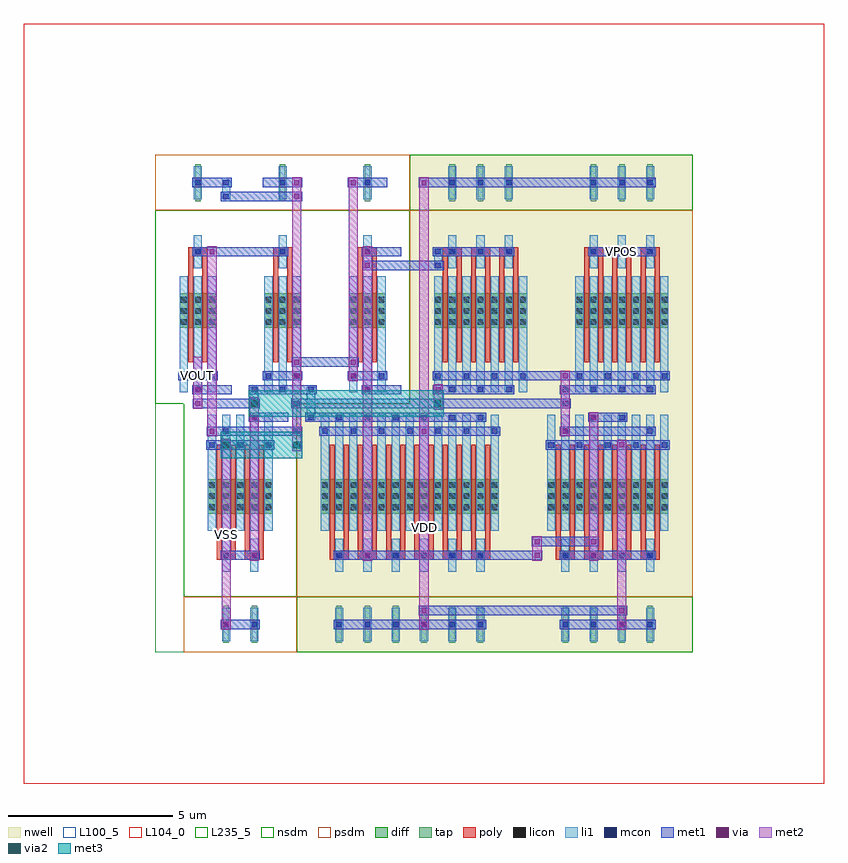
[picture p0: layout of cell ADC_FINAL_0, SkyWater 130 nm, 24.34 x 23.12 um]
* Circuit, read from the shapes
.subckt ADC_FINAL_0 VDD VOUT VPOS VSS
XM1 VOUT n1 VOUT VSS sky130_fd_pr__nfet_01v8 w=1.05 l=0.15 m=2
XM2 n1 n2 VSS VSS sky130_fd_pr__nfet_01v8 w=1.05 l=0.15 m=2
XM3 n2 n2 VSS VSS sky130_fd_pr__nfet_01v8 w=1.05 l=0.15 m=2
XM4 VOUT n1 VSS VSS sky130_fd_pr__nfet_01v8 w=1.05 l=0.15 m=2
XM5 n3 n3 VSS VSS sky130_fd_pr__nfet_01v8 w=1.05 l=0.15 m=2
XM6 VOUT n3 VDD VDD sky130_fd_pr__pfet_01v8 w=1.05 l=0.15 m=12
XM7 n2 n3 n4 VDD sky130_fd_pr__pfet_01v8 w=1.05 l=0.15 m=6
XM8 n4 n3 VDD VDD sky130_fd_pr__pfet_01v8 w=1.05 l=0.15 m=4
XM9 n3 n3 VDD VDD sky130_fd_pr__pfet_01v8 w=1.05 l=0.15 m=4
XM10 n1 VPOS n4 VDD sky130_fd_pr__pfet_01v8 w=1.05 l=0.15 m=6
.ends

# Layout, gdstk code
from math import pi, radians
import gdstk
lib = gdstk.Library(unit=1e-6, precision=1e-09)
def R(c, l, rs):  # rectangles x0, y0, x1, y1
    for r in rs: c.add(gdstk.rectangle(r[:2], r[2:], *l))
def A(c, l, x, y, w, h, nx, ny, dx, dy):  # array of equal rectangles
    R(c, l, [(x+i*dx, y+j*dy, x+i*dx+w, y+j*dy+h) for i in range(nx) for j in range(ny)])
def P(c, l, *ps):  # polygons
    for p in ps: c.add(gdstk.Polygon(p, *l))
nwell = (64, 20)
diff = (65, 20)
tap = (65, 44)
poly = (66, 20)
licon = (66, 44)
li1 = (67, 20)
mcon = (67, 44)
met1 = (68, 20)
via = (68, 44)
met2 = (69, 20)
via2 = (69, 44)
met3 = (70, 20)
nsdm = (93, 44)
psdm = (94, 20)
L100_5 = (100, 5)
L104_0 = (104, 0)
L235_5 = (235, 5)

scm_pmos_42993348_x2_y1_ = lib.new_cell('SCM_PMOS_42993348_X2_Y1_1678492655_1678492654')
R(scm_pmos_42993348_x2_y1_, nwell, [(0,0,5.16,7.56)])
R(scm_pmos_42993348_x2_y1_, diff, [(0.735,2.31,4.425,3.36)])
A(scm_pmos_42993348_x2_y1_, tap, 1.205, 6.16, 0.17, 1.12, 4, 1, 0.86, 0)
A(scm_pmos_42993348_x2_y1_, poly, 1, 1.26, 0.15, 3.36, 8, 1, 0.43, 0)
A(scm_pmos_42993348_x2_y1_, poly, 1, 4.485, 0.58, 0.27, 4, 1, 0.86, 0)
A(scm_pmos_42993348_x2_y1_, licon, 0.775, 2.39, 0.17, 0.17, 3, 3, 0.43, 0.34)
A(scm_pmos_42993348_x2_y1_, licon, 1.635, 2.39, 0.17, 0.17, 3, 3, 0.43, 0.34)
A(scm_pmos_42993348_x2_y1_, licon, 2.495, 2.39, 0.17, 0.17, 3, 3, 0.43, 0.34)
A(scm_pmos_42993348_x2_y1_, licon, 3.355, 2.39, 0.17, 0.17, 3, 3, 0.43, 0.34)
A(scm_pmos_42993348_x2_y1_, licon, 1.205, 4.535, 0.17, 0.17, 4, 2, 0.86, 2.1)
A(scm_pmos_42993348_x2_y1_, li1, 0.735, 0.335, 0.25, 3.53, 9, 1, 0.43, 0)
A(scm_pmos_42993348_x2_y1_, li1, 1.165, 4.115, 0.25, 1.01, 4, 2, 0.86, 2.1)
A(scm_pmos_42993348_x2_y1_, mcon, 0.775, 1.175, 0.17, 0.17, 5, 1, 0.86, 0)
A(scm_pmos_42993348_x2_y1_, mcon, 1.205, 4.535, 0.17, 0.17, 4, 2, 0.86, 2.1)
R(scm_pmos_42993348_x2_y1_, mcon, [(2.065,0.335,2.235,0.505), (2.925,0.335,3.095,0.505), (1.205,0.755,1.375,0.925), (3.785,0.755,3.955,0.925)])
R(scm_pmos_42993348_x2_y1_, met1, [(1.98,0.28,3.18,0.56), (1.12,0.7,4.04,0.98), (0.69,1.12,4.47,1.4), (1.12,4.48,4.04,4.76), (1.12,6.58,4.04,6.86)])
R(scm_pmos_42993348_x2_y1_, via, [(2.075,0.345,2.225,0.495), (2.935,1.185,3.085,1.335), (2.075,4.545,2.225,4.695), (2.935,6.645,3.085,6.795)])
R(scm_pmos_42993348_x2_y1_, met2, [(2.01,0.26,2.29,4.78), (2.87,1.1,3.15,6.88)])
R(scm_pmos_42993348_x2_y1_, nsdm, [(0,5.88,5.16,7.56)])
R(scm_pmos_42993348_x2_y1_, psdm, [(0,0,5.16,5.88)])
R(scm_pmos_42993348_x2_y1_, L100_5, [(0,0,5.16,7.56)])

pmos_s_81354572_x6_y1_16 = lib.new_cell('PMOS_S_81354572_X6_Y1_1678492654_1678492654')
R(pmos_s_81354572_x6_y1_16, nwell, [(0,0,6.88,7.56)])
R(pmos_s_81354572_x6_y1_16, diff, [(0.735,2.31,6.145,3.36)])
A(pmos_s_81354572_x6_y1_16, tap, 1.205, 6.16, 0.17, 1.12, 6, 1, 0.86, 0)
A(pmos_s_81354572_x6_y1_16, poly, 1, 1.26, 0.15, 3.36, 12, 1, 0.43, 0)
A(pmos_s_81354572_x6_y1_16, poly, 1, 4.485, 0.58, 0.27, 6, 1, 0.86, 0)
A(pmos_s_81354572_x6_y1_16, licon, 0.775, 2.39, 0.17, 0.17, 3, 3, 0.43, 0.34)
A(pmos_s_81354572_x6_y1_16, licon, 1.635, 2.39, 0.17, 0.17, 3, 3, 0.43, 0.34)
A(pmos_s_81354572_x6_y1_16, licon, 2.495, 2.39, 0.17, 0.17, 3, 3, 0.43, 0.34)
A(pmos_s_81354572_x6_y1_16, licon, 3.355, 2.39, 0.17, 0.17, 3, 3, 0.43, 0.34)
A(pmos_s_81354572_x6_y1_16, licon, 4.215, 2.39, 0.17, 0.17, 3, 3, 0.43, 0.34)
A(pmos_s_81354572_x6_y1_16, licon, 5.075, 2.39, 0.17, 0.17, 3, 3, 0.43, 0.34)
A(pmos_s_81354572_x6_y1_16, licon, 1.205, 4.535, 0.17, 0.17, 6, 2, 0.86, 2.1)
A(pmos_s_81354572_x6_y1_16, li1, 0.735, 0.335, 0.25, 3.53, 13, 1, 0.43, 0)
A(pmos_s_81354572_x6_y1_16, li1, 1.165, 4.115, 0.25, 1.01, 6, 2, 0.86, 2.1)
A(pmos_s_81354572_x6_y1_16, mcon, 1.205, 0.335, 0.17, 0.17, 6, 2, 0.86, 4.2)
A(pmos_s_81354572_x6_y1_16, mcon, 0.775, 0.755, 0.17, 0.17, 7, 1, 0.86, 0)
A(pmos_s_81354572_x6_y1_16, mcon, 1.205, 6.635, 0.17, 0.17, 6, 1, 0.86, 0)
R(pmos_s_81354572_x6_y1_16, met1, [(1.12,0.28,5.76,0.56), (0.69,0.7,6.19,0.98), (1.12,4.48,5.76,4.76), (1.12,6.58,5.76,6.86)])
R(pmos_s_81354572_x6_y1_16, via, [(3.795,0.765,3.945,0.915), (3.795,6.645,3.945,6.795)])
R(pmos_s_81354572_x6_y1_16, met2, [(3.73,0.68,4.01,6.88)])
R(pmos_s_81354572_x6_y1_16, nsdm, [(0,5.88,6.88,7.56)])
R(pmos_s_81354572_x6_y1_16, psdm, [(0,0,6.88,5.88)])
R(pmos_s_81354572_x6_y1_16, L100_5, [(0,0,6.88,7.56)])

cmb_pmos_2_81333957_0_0_ = lib.new_cell('CMB_PMOS_2_81333957_0_0_1678492654')
R(cmb_pmos_2_81333957_0_0_, met1, [(7.15,4.06,7.47,4.34), (7.15,4.06,7.47,4.34), (7.31,4.06,9.03,4.34), (8.87,4.06,9.19,4.34), (8.87,4.06,9.19,4.34), (5.59,4.48,7.31,4.76), (7.15,4.48,7.47,4.76), (7.15,4.48,7.47,4.76), (3.71,6.16,4.03,6.44), (3.71,6.16,4.03,6.44), (3.87,6.16,9.89,6.44), (9.73,6.16,10.05,6.44), (9.73,6.16,10.05,6.44)])
P(cmb_pmos_2_81333957_0_0_, met1, [(0,0),(0,0),(0,0),(0,0)],
  [(0,0),(0,0),(0,0),(0,0)],
  [(0,0),(0,0),(0,0),(0,0)])
R(cmb_pmos_2_81333957_0_0_, via, [(7.235,4.125,7.385,4.275), (7.235,4.125,7.385,4.275), (8.955,4.125,9.105,4.275), (8.955,4.125,9.105,4.275), (7.235,4.545,7.385,4.695), (7.235,4.545,7.385,4.695), (3.795,6.225,3.945,6.375), (3.795,6.225,3.945,6.375), (9.815,6.225,9.965,6.375), (9.815,6.225,9.965,6.375)])
R(cmb_pmos_2_81333957_0_0_, met2, [(7.17,4.04,7.45,4.36), (7.17,4.04,7.45,4.36), (8.89,4.04,9.17,4.36), (8.89,4.04,9.17,4.36), (7.17,4.2,7.45,4.62), (7.17,4.46,7.45,4.78), (7.17,4.46,7.45,4.78), (3.73,6.14,4.01,6.46), (3.73,6.14,4.01,6.46), (9.75,6.14,10.03,6.46), (9.75,6.14,10.03,6.46)])
P(cmb_pmos_2_81333957_0_0_, met2, [(0,0),(0,0),(0,0),(0,0)],
  [(0,0),(0,0),(0,0),(0,0)],
  [(0,0),(0,0),(0,0),(0,0)])
R(cmb_pmos_2_81333957_0_0_, L235_5, [(0,0,12.04,7.56)])
cmb_pmos_2_81333957_0_0_.add(gdstk.Reference(scm_pmos_42993348_x2_y1_, (6.88,0)))
cmb_pmos_2_81333957_0_0_.add(gdstk.Reference(pmos_s_81354572_x6_y1_16, (0,0)))

scm_nmos_43308780_x1_y1_ = lib.new_cell('SCM_NMOS_43308780_X1_Y1_1678492659')
R(scm_nmos_43308780_x1_y1_, diff, [(0.735,2.31,2.705,3.36)])
R(scm_nmos_43308780_x1_y1_, tap, [(1.205,6.16,1.375,7.28), (2.065,6.16,2.235,7.28)])
A(scm_nmos_43308780_x1_y1_, poly, 1, 1.26, 0.15, 3.36, 4, 1, 0.43, 0)
R(scm_nmos_43308780_x1_y1_, poly, [(1,4.485,1.58,4.755), (1.86,4.485,2.44,4.755)])
A(scm_nmos_43308780_x1_y1_, licon, 0.775, 2.39, 0.17, 0.17, 3, 3, 0.43, 0.34)
A(scm_nmos_43308780_x1_y1_, licon, 1.635, 2.39, 0.17, 0.17, 3, 3, 0.43, 0.34)
R(scm_nmos_43308780_x1_y1_, licon, [(1.205,4.535,1.375,4.705), (2.065,4.535,2.235,4.705), (1.205,6.635,1.375,6.805), (2.065,6.635,2.235,6.805)])
A(scm_nmos_43308780_x1_y1_, li1, 0.735, 0.335, 0.25, 3.53, 5, 1, 0.43, 0)
R(scm_nmos_43308780_x1_y1_, li1, [(1.165,4.115,1.415,5.125), (2.025,4.115,2.275,5.125), (1.165,6.215,1.415,7.225), (2.025,6.215,2.275,7.225)])
A(scm_nmos_43308780_x1_y1_, mcon, 0.775, 1.175, 0.17, 0.17, 3, 1, 0.86, 0)
R(scm_nmos_43308780_x1_y1_, mcon, [(1.205,0.335,1.375,0.505), (2.065,0.755,2.235,0.925), (1.205,4.535,1.375,4.705), (2.065,4.535,2.235,4.705), (1.205,6.635,1.375,6.805), (2.065,6.635,2.235,6.805)])
R(scm_nmos_43308780_x1_y1_, met1, [(0.26,0.28,1.46,0.56), (1.12,0.7,2.32,0.98), (0.69,1.12,2.75,1.4), (1.12,4.48,2.32,4.76), (1.12,6.58,2.32,6.86)])
R(scm_nmos_43308780_x1_y1_, via, [(1.215,0.345,1.365,0.495), (2.075,1.185,2.225,1.335), (1.215,4.545,1.365,4.695), (2.075,6.645,2.225,6.795)])
R(scm_nmos_43308780_x1_y1_, met2, [(1.15,0.26,1.43,4.78), (2.01,1.1,2.29,6.88)])
R(scm_nmos_43308780_x1_y1_, nsdm, [(0,0,3.44,5.88)])
R(scm_nmos_43308780_x1_y1_, psdm, [(0,5.88,3.44,7.56)])
R(scm_nmos_43308780_x1_y1_, L100_5, [(0,0,3.44,7.56)])

dcl_nmos_s_28285743_x1_y = lib.new_cell('DCL_NMOS_S_28285743_X1_Y1_1678492656')
R(dcl_nmos_s_28285743_x1_y, diff, [(0.735,2.31,1.845,3.36)])
R(dcl_nmos_s_28285743_x1_y, tap, [(1.205,6.16,1.375,7.28)])
R(dcl_nmos_s_28285743_x1_y, poly, [(1,1.26,1.15,4.62), (1.43,1.26,1.58,4.62), (1,4.485,1.58,4.755)])
A(dcl_nmos_s_28285743_x1_y, licon, 0.775, 2.39, 0.17, 0.17, 3, 3, 0.43, 0.34)
R(dcl_nmos_s_28285743_x1_y, licon, [(1.205,4.535,1.375,4.705), (1.205,6.635,1.375,6.805)])
A(dcl_nmos_s_28285743_x1_y, li1, 0.735, 0.335, 0.25, 3.53, 3, 1, 0.43, 0)
R(dcl_nmos_s_28285743_x1_y, li1, [(1.165,4.115,1.415,5.125), (1.165,6.215,1.415,7.225)])
R(dcl_nmos_s_28285743_x1_y, mcon, [(1.205,0.335,1.375,0.505), (0.775,0.755,0.945,0.925), (1.635,0.755,1.805,0.925), (1.205,4.535,1.375,4.705), (1.205,6.635,1.375,6.805)])
R(dcl_nmos_s_28285743_x1_y, met1, [(0.26,0.28,1.46,0.56), (0.69,0.7,1.89,0.98), (0.26,4.48,1.46,4.76), (0.69,6.58,1.89,6.86)])
R(dcl_nmos_s_28285743_x1_y, via, [(1.215,0.345,1.365,0.495), (1.645,0.765,1.795,0.915), (1.215,4.545,1.365,4.695), (1.645,6.645,1.795,6.795)])
R(dcl_nmos_s_28285743_x1_y, met2, [(1.15,0.26,1.43,4.78), (1.58,0.68,1.86,6.88)])
R(dcl_nmos_s_28285743_x1_y, nsdm, [(0,0,2.58,5.88)])
R(dcl_nmos_s_28285743_x1_y, psdm, [(0,5.88,2.58,7.56)])
R(dcl_nmos_s_28285743_x1_y, L100_5, [(0,0,2.58,7.56)])

nmos_s_54487678_x1_y1_16 = lib.new_cell('NMOS_S_54487678_X1_Y1_1678492657')
R(nmos_s_54487678_x1_y1_16, diff, [(0.735,2.31,1.845,3.36)])
R(nmos_s_54487678_x1_y1_16, tap, [(1.205,6.16,1.375,7.28)])
R(nmos_s_54487678_x1_y1_16, poly, [(1,1.26,1.15,4.62), (1.43,1.26,1.58,4.62), (1,4.485,1.58,4.755)])
A(nmos_s_54487678_x1_y1_16, licon, 0.775, 2.39, 0.17, 0.17, 3, 3, 0.43, 0.34)
R(nmos_s_54487678_x1_y1_16, licon, [(1.205,4.535,1.375,4.705), (1.205,6.635,1.375,6.805)])
A(nmos_s_54487678_x1_y1_16, li1, 0.735, 0.335, 0.25, 3.53, 3, 1, 0.43, 0)
R(nmos_s_54487678_x1_y1_16, li1, [(1.165,4.115,1.415,5.125), (1.165,6.215,1.415,7.225)])
R(nmos_s_54487678_x1_y1_16, mcon, [(1.205,0.335,1.375,0.505), (0.775,0.755,0.945,0.925), (1.635,0.755,1.805,0.925), (1.205,4.535,1.375,4.705), (1.205,6.635,1.375,6.805)])
R(nmos_s_54487678_x1_y1_16, met1, [(0.26,0.28,1.46,0.56), (0.69,0.7,1.89,0.98), (0.26,4.48,1.46,4.76), (0.69,6.58,1.89,6.86)])
R(nmos_s_54487678_x1_y1_16, via, [(1.645,0.765,1.795,0.915), (1.645,6.645,1.795,6.795)])
R(nmos_s_54487678_x1_y1_16, met2, [(1.58,0.68,1.86,6.88)])
R(nmos_s_54487678_x1_y1_16, nsdm, [(0,0,2.58,5.88)])
R(nmos_s_54487678_x1_y1_16, psdm, [(0,5.88,2.58,7.56)])
R(nmos_s_54487678_x1_y1_16, L100_5, [(0,0,2.58,7.56)])

dcap_nmos_b_17613965_x1_ = lib.new_cell('DCAP_NMOS_B_17613965_X1_Y1_1678492655')
R(dcap_nmos_b_17613965_x1_, diff, [(0.735,2.31,1.845,3.36)])
R(dcap_nmos_b_17613965_x1_, tap, [(1.205,6.16,1.375,7.28)])
R(dcap_nmos_b_17613965_x1_, poly, [(1,1.26,1.15,4.62), (1.43,1.26,1.58,4.62), (1,4.485,1.58,4.755)])
A(dcap_nmos_b_17613965_x1_, licon, 0.775, 2.39, 0.17, 0.17, 3, 3, 0.43, 0.34)
R(dcap_nmos_b_17613965_x1_, licon, [(1.205,4.535,1.375,4.705), (1.205,6.635,1.375,6.805)])
A(dcap_nmos_b_17613965_x1_, li1, 0.735, 0.335, 0.25, 3.53, 3, 1, 0.43, 0)
R(dcap_nmos_b_17613965_x1_, li1, [(1.165,4.115,1.415,5.125), (1.165,6.215,1.415,7.225)])
R(dcap_nmos_b_17613965_x1_, mcon, [(1.205,0.335,1.375,0.505), (0.775,0.755,0.945,0.925), (1.635,0.755,1.805,0.925), (1.205,4.535,1.375,4.705), (1.205,6.635,1.375,6.805)])
R(dcap_nmos_b_17613965_x1_, met1, [(0.26,0.28,1.46,0.56), (0.69,0.7,1.89,0.98), (0.26,4.48,1.46,4.76), (0.26,6.58,1.46,6.86)])
R(dcap_nmos_b_17613965_x1_, via, [(1.215,0.345,1.365,0.495), (1.215,0.765,1.365,0.915)])
R(dcap_nmos_b_17613965_x1_, met2, [(1.15,0.26,1.43,1.42)])
R(dcap_nmos_b_17613965_x1_, nsdm, [(0,0,2.58,5.88)])
R(dcap_nmos_b_17613965_x1_, psdm, [(0,5.88,2.58,7.56)])
R(dcap_nmos_b_17613965_x1_, L100_5, [(0,0,2.58,7.56)])

pmos_4t_25753472_x3_y1_1 = lib.new_cell('PMOS_4T_25753472_X3_Y1_1678492658')
R(pmos_4t_25753472_x3_y1_1, nwell, [(0,0,4.3,7.56)])
R(pmos_4t_25753472_x3_y1_1, diff, [(0.735,2.31,3.565,3.36)])
A(pmos_4t_25753472_x3_y1_1, tap, 1.205, 6.16, 0.17, 1.12, 3, 1, 0.86, 0)
A(pmos_4t_25753472_x3_y1_1, poly, 1, 1.26, 0.15, 3.36, 6, 1, 0.43, 0)
A(pmos_4t_25753472_x3_y1_1, poly, 1, 4.485, 0.58, 0.27, 3, 1, 0.86, 0)
A(pmos_4t_25753472_x3_y1_1, licon, 0.775, 2.39, 0.17, 0.17, 3, 3, 0.43, 0.34)
A(pmos_4t_25753472_x3_y1_1, licon, 1.635, 2.39, 0.17, 0.17, 3, 3, 0.43, 0.34)
A(pmos_4t_25753472_x3_y1_1, licon, 2.495, 2.39, 0.17, 0.17, 3, 3, 0.43, 0.34)
A(pmos_4t_25753472_x3_y1_1, licon, 1.205, 4.535, 0.17, 0.17, 3, 2, 0.86, 2.1)
A(pmos_4t_25753472_x3_y1_1, li1, 0.735, 0.335, 0.25, 3.53, 7, 1, 0.43, 0)
A(pmos_4t_25753472_x3_y1_1, li1, 1.165, 4.115, 0.25, 1.01, 3, 2, 0.86, 2.1)
A(pmos_4t_25753472_x3_y1_1, mcon, 1.205, 0.335, 0.17, 0.17, 3, 2, 0.86, 4.2)
A(pmos_4t_25753472_x3_y1_1, mcon, 0.775, 0.755, 0.17, 0.17, 4, 1, 0.86, 0)
A(pmos_4t_25753472_x3_y1_1, mcon, 1.205, 6.635, 0.17, 0.17, 3, 1, 0.86, 0)
R(pmos_4t_25753472_x3_y1_1, met1, [(1.12,0.28,3.18,0.56), (0.69,0.7,3.61,0.98), (1.12,4.48,3.18,4.76), (1.12,6.58,3.18,6.86)])
R(pmos_4t_25753472_x3_y1_1, nsdm, [(0,5.88,4.3,7.56)])
R(pmos_4t_25753472_x3_y1_1, psdm, [(0,0,4.3,5.88)])
R(pmos_4t_25753472_x3_y1_1, L100_5, [(0,0,4.3,7.56)])

adc_final_0 = lib.new_cell('ADC_FINAL_0')
R(adc_final_0, li1, [(4.175,6.635,4.425,6.805), (4.175,6.635,4.425,6.805), (4.175,6.72,4.425,7.56), (4.605,7.055,4.855,7.225), (4.605,7.055,4.855,7.225), (4.605,7.14,4.855,7.98), (2.885,7.475,3.135,7.645), (2.885,7.475,3.135,7.645), (2.885,7.475,3.135,7.645), (2.885,7.475,3.135,7.645), (4.175,7.475,4.425,7.645), (4.175,7.475,4.425,7.645), (12.345,7.475,12.595,7.645), (12.345,7.475,12.595,7.645), (2.885,7.56,3.135,7.98), (12.345,7.56,12.595,7.98), (2.885,7.895,3.135,8.065), (2.885,7.895,3.135,8.065), (2.885,7.895,3.135,8.065), (2.885,7.895,3.135,8.065), (4.605,7.895,4.855,8.065), (4.605,7.895,4.855,8.065), (12.345,7.895,12.595,8.065), (12.345,7.895,12.595,8.065), (8.475,11.675,8.725,11.845), (8.475,11.675,8.725,11.845), (8.475,11.76,8.725,12.18), (8.475,12.095,8.725,12.265), (8.475,12.095,8.725,12.265), (2.025,13.775,2.275,13.945), (2.025,13.775,2.275,13.945), (2.025,13.86,2.275,14.28), (2.025,14.195,2.275,14.365), (2.025,14.195,2.275,14.365)])
R(adc_final_0, mcon, [(4.215,6.635,4.385,6.805), (4.215,6.635,4.385,6.805), (4.645,7.055,4.815,7.225), (4.645,7.055,4.815,7.225), (2.925,7.475,3.095,7.645), (2.925,7.475,3.095,7.645), (2.925,7.475,3.095,7.645), (2.925,7.475,3.095,7.645), (4.215,7.475,4.385,7.645), (4.215,7.475,4.385,7.645), (12.385,7.475,12.555,7.645), (12.385,7.475,12.555,7.645), (2.925,7.895,3.095,8.065), (2.925,7.895,3.095,8.065), (2.925,7.895,3.095,8.065), (2.925,7.895,3.095,8.065), (4.645,7.895,4.815,8.065), (4.645,7.895,4.815,8.065), (12.385,7.895,12.555,8.065), (12.385,7.895,12.555,8.065), (8.515,11.675,8.685,11.845), (8.515,11.675,8.685,11.845), (8.515,12.095,8.685,12.265), (8.515,12.095,8.685,12.265), (2.065,13.775,2.235,13.945), (2.065,13.775,2.235,13.945), (2.065,14.195,2.235,14.365), (2.065,14.195,2.235,14.365)])
R(adc_final_0, met1, [(6.29,2.8,6.61,3.08), (6.29,2.8,6.61,3.08), (6.29,2.8,6.61,3.08), (6.29,2.8,6.61,3.08), (1.56,6.58,1.88,6.86), (1.56,6.58,1.88,6.86), (1.56,6.58,1.88,6.86), (1.56,6.58,1.88,6.86), (1.56,6.58,1.88,6.86), (1.56,6.58,1.88,6.86), (1.72,6.58,2.15,6.86), (3.01,6.58,4.3,6.86), (4.13,6.58,4.47,6.86), (4.13,6.58,4.47,6.86), (12.31,6.58,12.63,6.86), (12.31,6.58,12.63,6.86), (4.56,7,4.9,7.28), (4.56,7,4.9,7.28), (4.73,7,5.59,7.28), (1.13,7.42,1.45,7.7), (1.13,7.42,1.45,7.7), (1.13,7.42,1.45,7.7), (1.13,7.42,1.45,7.7), (1.29,7.42,3.01,7.7), (2.84,7.42,3.18,7.7), (2.84,7.42,3.18,7.7), (2.84,7.42,3.18,7.7), (2.84,7.42,3.18,7.7), (4.13,7.42,4.47,7.7), (4.13,7.42,4.47,7.7), (4.3,7.42,12.47,7.7), (12.3,7.42,12.64,7.7), (12.3,7.42,12.64,7.7), (2.84,7.84,3.18,8.12), (2.84,7.84,3.18,8.12), (2.84,7.84,3.18,8.12), (2.84,7.84,3.18,8.12), (3.87,7.84,4.73,8.12), (4.56,7.84,4.9,8.12), (4.56,7.84,4.9,8.12), (8.44,7.84,8.76,8.12), (8.44,7.84,8.76,8.12), (8.6,7.84,9.03,8.12), (12.3,7.84,12.64,8.12), (12.3,7.84,12.64,8.12), (12.47,7.84,13.33,8.12), (11.18,8.26,12.9,8.54), (12.31,8.26,12.63,8.54), (12.31,8.26,12.63,8.54), (4.14,8.68,4.46,8.96), (4.14,8.68,4.46,8.96), (4.14,8.68,4.46,8.96), (4.14,8.68,4.46,8.96), (4.3,8.68,6.02,8.96), (5.86,8.68,6.18,8.96), (5.86,8.68,6.18,8.96), (5.86,8.68,6.18,8.96), (5.86,8.68,6.18,8.96), (6.29,11.62,6.61,11.9), (6.29,11.62,6.61,11.9), (6.45,11.62,8.6,11.9), (8.43,11.62,8.77,11.9), (8.43,11.62,8.77,11.9), (1.56,12.04,1.88,12.32), (1.56,12.04,1.88,12.32), (1.56,12.04,1.88,12.32), (1.56,12.04,1.88,12.32), (1.56,12.04,1.88,12.32), (1.56,12.04,1.88,12.32), (2.15,12.04,3.01,12.32), (8.43,12.04,8.77,12.32), (8.43,12.04,8.77,12.32), (8.6,12.04,9.03,12.32), (1.98,13.72,2.32,14), (1.98,13.72,2.32,14), (2.15,13.72,4.3,14), (4.14,13.72,4.46,14), (4.14,13.72,4.46,14), (1.98,14.14,2.32,14.42), (1.98,14.14,2.32,14.42), (8.01,14.14,8.33,14.42), (8.01,14.14,8.33,14.42), (8.01,14.14,8.33,14.42), (8.01,14.14,8.33,14.42), (8.17,14.14,9.03,14.42), (10.75,14.14,13.33,14.42)])
P(adc_final_0, met1, [(0,0),(0,0),(0,0),(0,0)],
  [(0,0),(0,0),(0,0),(0,0)],
  [(0,0),(0,0),(0,0),(0,0)],
  [(0,0),(0,0),(0,0),(0,0)],
  [(0,0),(0,0),(0,0),(0,0)],
  [(0,0),(0,0),(0,0),(0,0)],
  [(0,0),(0,0),(0,0),(0,0)],
  [(0,0),(0,0),(0,0),(0,0)],
  [(0,0),(0,0),(0,0),(0,0)],
  [(0,0),(0,0),(0,0),(0,0)],
  [(0,0),(0,0),(0,0),(0,0)],
  [(0,0),(0,0),(0,0),(0,0)],
  [(0,0),(0,0),(0,0),(0,0)],
  [(0,0),(0,0),(0,0),(0,0)],
  [(0,0),(0,0),(0,0),(0,0)],
  [(0,0),(0,0),(0,0),(0,0)],
  [(0,0),(0,0),(0,0),(0,0)],
  [(0,0),(0,0),(0,0),(0,0)],
  [(0,0),(0,0),(0,0),(0,0)],
  [(0,0),(0,0),(0,0),(0,0)])
R(adc_final_0, via, [(6.375,2.865,6.525,3.015), (6.375,2.865,6.525,3.015), (6.375,2.865,6.525,3.015), (6.375,2.865,6.525,3.015), (1.645,6.645,1.795,6.795), (1.645,6.645,1.795,6.795), (1.645,6.645,1.795,6.795), (1.645,6.645,1.795,6.795), (1.645,6.645,1.795,6.795), (1.645,6.645,1.795,6.795), (12.395,6.645,12.545,6.795), (12.395,6.645,12.545,6.795), (1.215,7.485,1.365,7.635), (1.215,7.485,1.365,7.635), (1.215,7.485,1.365,7.635), (1.215,7.485,1.365,7.635), (8.525,7.905,8.675,8.055), (8.525,7.905,8.675,8.055), (12.395,8.325,12.545,8.475), (12.395,8.325,12.545,8.475), (4.225,8.745,4.375,8.895), (4.225,8.745,4.375,8.895), (4.225,8.745,4.375,8.895), (4.225,8.745,4.375,8.895), (5.945,8.745,6.095,8.895), (5.945,8.745,6.095,8.895), (5.945,8.745,6.095,8.895), (5.945,8.745,6.095,8.895), (6.375,11.685,6.525,11.835), (6.375,11.685,6.525,11.835), (1.645,12.105,1.795,12.255), (1.645,12.105,1.795,12.255), (1.645,12.105,1.795,12.255), (1.645,12.105,1.795,12.255), (1.645,12.105,1.795,12.255), (1.645,12.105,1.795,12.255), (4.225,13.785,4.375,13.935), (4.225,13.785,4.375,13.935), (8.095,14.205,8.245,14.355), (8.095,14.205,8.245,14.355), (8.095,14.205,8.245,14.355), (8.095,14.205,8.245,14.355)])
R(adc_final_0, met2, [(6.31,2.78,6.59,3.1), (6.31,2.78,6.59,3.1), (6.31,2.78,6.59,3.1), (6.31,2.78,6.59,3.1), (6.31,2.94,6.59,7.98), (2.01,6.115,2.29,6.485), (2.01,6.115,2.29,6.485), (2.01,6.115,2.29,6.485), (2.01,6.115,2.29,6.485), (2.01,6.115,2.29,6.485), (2.01,6.115,2.29,6.485), (4.16,6.115,4.44,6.485), (4.16,6.115,4.44,6.485), (4.16,6.115,4.44,6.485), (4.16,6.115,4.44,6.485), (4.16,6.115,4.44,6.485), (4.16,6.115,4.44,6.485), (4.16,6.3,4.44,8.4), (1.58,6.56,1.86,6.88), (1.58,6.56,1.86,6.88), (1.58,6.56,1.86,6.88), (1.58,6.56,1.86,6.88), (1.58,6.56,1.86,6.88), (1.58,6.56,1.86,6.88), (12.33,6.56,12.61,6.88), (12.33,6.56,12.61,6.88), (1.58,6.72,1.86,12.18), (8.03,6.72,8.31,14.28), (12.33,6.72,12.61,8.4), (2.87,7.14,3.15,7.56), (2.87,7.375,3.15,7.745), (2.87,7.375,3.15,7.745), (8.46,7.375,8.74,7.745), (8.46,7.375,8.74,7.745), (1.15,7.4,1.43,7.72), (1.15,7.4,1.43,7.72), (1.15,7.4,1.43,7.72), (1.15,7.4,1.43,7.72), (1.15,7.56,1.43,7.98), (8.46,7.56,8.74,7.98), (8.46,7.82,8.74,8.14), (8.46,7.82,8.74,8.14), (12.33,8.24,12.61,8.56), (12.33,8.24,12.61,8.56), (4.16,8.66,4.44,8.98), (4.16,8.66,4.44,8.98), (4.16,8.66,4.44,8.98), (4.16,8.66,4.44,8.98), (5.88,8.66,6.16,8.98), (5.88,8.66,6.16,8.98), (5.88,8.66,6.16,8.98), (5.88,8.66,6.16,8.98), (6.31,11.6,6.59,11.92), (6.31,11.6,6.59,11.92), (1.58,12.02,1.86,12.34), (1.58,12.02,1.86,12.34), (1.58,12.02,1.86,12.34), (1.58,12.02,1.86,12.34), (1.58,12.02,1.86,12.34), (1.58,12.02,1.86,12.34), (4.16,13.7,4.44,14.02), (4.16,13.7,4.44,14.02), (8.03,14.12,8.31,14.44), (8.03,14.12,8.31,14.44), (8.03,14.12,8.31,14.44), (8.03,14.12,8.31,14.44)])
P(adc_final_0, met2, [(0,0),(0,0),(0,0),(0,0)],
  [(0,0),(0,0),(0,0),(0,0)],
  [(0,0),(0,0),(0,0),(0,0)],
  [(0,0),(0,0),(0,0),(0,0)],
  [(0,0),(0,0),(0,0),(0,0)],
  [(0,0),(0,0),(0,0),(0,0)],
  [(0,0),(0,0),(0,0),(0,0)],
  [(0,0),(0,0),(0,0),(0,0)],
  [(0,0),(0,0),(0,0),(0,0)],
  [(0,0),(0,0),(0,0),(0,0)],
  [(0,0),(0,0),(0,0),(0,0)],
  [(0,0),(0,0),(0,0),(0,0)],
  [(0,0),(0,0),(0,0),(0,0)],
  [(0,0),(0,0),(0,0),(0,0)],
  [(0,0),(0,0),(0,0),(0,0)],
  [(0,0),(0,0),(0,0),(0,0)])
R(adc_final_0, via2, [(2.05,6.2,2.25,6.4), (2.05,6.2,2.25,6.4), (2.05,6.2,2.25,6.4), (2.05,6.2,2.25,6.4), (2.05,6.2,2.25,6.4), (2.05,6.2,2.25,6.4), (4.2,6.2,4.4,6.4), (4.2,6.2,4.4,6.4), (4.2,6.2,4.4,6.4), (4.2,6.2,4.4,6.4), (4.2,6.2,4.4,6.4), (4.2,6.2,4.4,6.4), (2.91,7.46,3.11,7.66), (2.91,7.46,3.11,7.66), (8.5,7.46,8.7,7.66), (8.5,7.46,8.7,7.66)])
R(adc_final_0, met3, [(1.985,5.9,2.315,6.7), (1.985,5.9,2.315,6.7), (1.985,5.9,2.315,6.7), (1.985,5.9,2.315,6.7), (1.985,5.9,2.315,6.7), (1.985,5.9,2.315,6.7), (2.15,5.9,4.3,6.7), (4.135,5.9,4.465,6.7), (4.135,5.9,4.465,6.7), (4.135,5.9,4.465,6.7), (4.135,5.9,4.465,6.7), (4.135,5.9,4.465,6.7), (4.135,5.9,4.465,6.7), (2.845,7.16,3.175,7.96), (2.845,7.16,3.175,7.96), (3.01,7.16,8.6,7.96), (8.435,7.16,8.765,7.96), (8.435,7.16,8.765,7.96)])
R(adc_final_0, L104_0, [(-4,-4,20.34,19.12)])
R(adc_final_0, L235_5, [(0,0,16.34,15.12)])
adc_final_0.add(gdstk.Reference(cmb_pmos_2_81333957_0_0_, (4.3,7.56), x_reflection=True))
adc_final_0.add(gdstk.Reference(scm_nmos_43308780_x1_y1_, (4.3,7.56), rotation=pi))
adc_final_0.add(gdstk.Reference(dcl_nmos_s_28285743_x1_y, (7.74,7.56), rotation=pi, x_reflection=True))
adc_final_0.add(gdstk.Reference(nmos_s_54487678_x1_y1_16, (2.58,7.56)))
adc_final_0.add(gdstk.Reference(dcap_nmos_b_17613965_x1_, (2.58,7.56), rotation=pi, x_reflection=True))
adc_final_0.add(gdstk.Reference(pmos_4t_25753472_x3_y1_1, (7.74,7.56)))
adc_final_0.add(gdstk.Reference(pmos_4t_25753472_x3_y1_1, (16.34,7.56), rotation=pi, x_reflection=True))
adc_final_0.add(gdstk.Label('VOUT', (1.29,8.4), layer=69, texttype=5))
adc_final_0.add(gdstk.Label('VDD', (8.17,3.78), layer=69, texttype=5))
adc_final_0.add(gdstk.Label('VSS', (2.15,3.57), layer=69, texttype=5))
adc_final_0.add(gdstk.Label('VPOS', (14.19,12.18), layer=68, texttype=5))

lib.write_gds('ADC_FINAL_0.gds')
